VERSION 5.7 ;
  NOWIREEXTENSIONATPIN ON ;
  DIVIDERCHAR "/" ;
  BUSBITCHARS "[]" ;
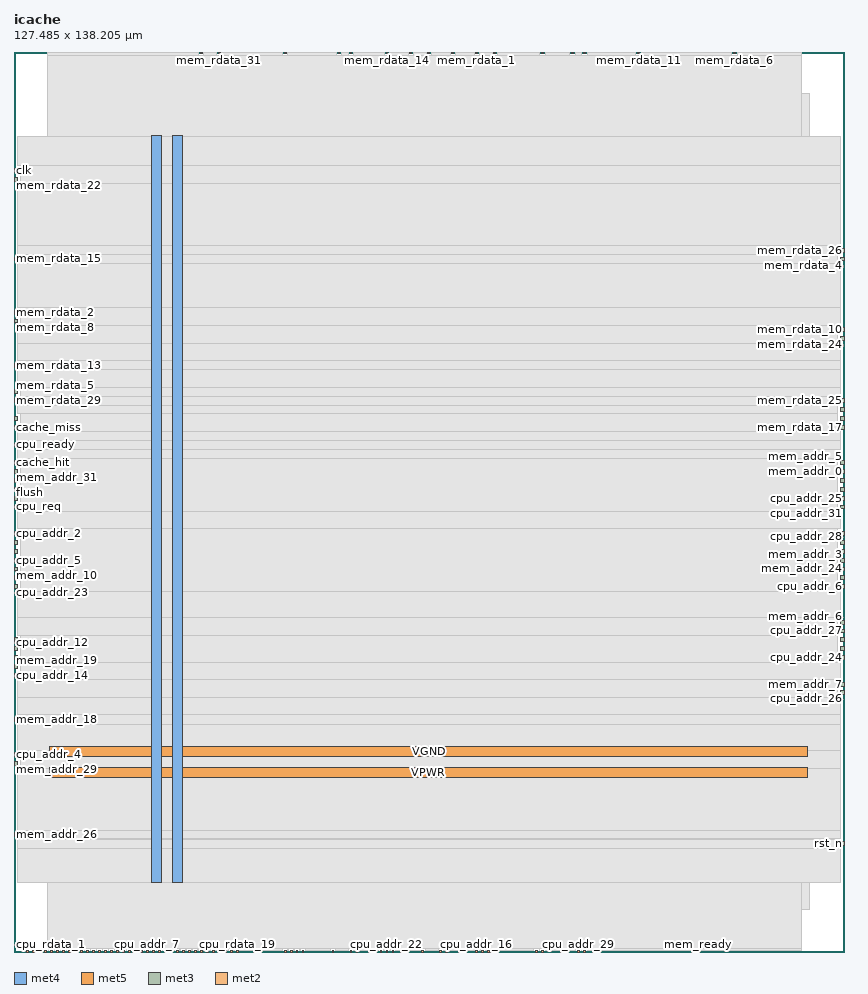
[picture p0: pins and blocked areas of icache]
MACRO icache
  CLASS BLOCK ;
  FOREIGN icache ;
  ORIGIN 0.000 0.000 ;
  SIZE 127.485 BY 138.205 ;
  PIN VGND
    DIRECTION INOUT ;
    USE GROUND ;
    PORT
      LAYER met4 ;
        RECT 24.340 10.640 25.940 125.360 ;
    END
    PORT
      LAYER met5 ;
        RECT 5.520 30.030 121.900 31.630 ;
    END
  END VGND
  PIN VPWR
    DIRECTION INOUT ;
    USE POWER ;
    PORT
      LAYER met4 ;
        RECT 21.040 10.640 22.640 125.360 ;
    END
    PORT
      LAYER met5 ;
        RECT 5.520 26.730 121.900 28.330 ;
    END
  END VPWR
  PIN cache_hit
    DIRECTION OUTPUT ;
    USE SIGNAL ;
    ANTENNAGATEAREA 0.434700 ;
    ANTENNADIFFAREA 1.137600 ;
    PORT
      LAYER met3 ;
        RECT 0.000 74.840 0.600 75.440 ;
    END
  END cache_hit
  PIN cache_miss
    DIRECTION OUTPUT ;
    USE SIGNAL ;
    ANTENNAGATEAREA 0.434700 ;
    ANTENNADIFFAREA 1.137600 ;
    PORT
      LAYER met3 ;
        RECT 0.000 80.280 0.600 80.880 ;
    END
  END cache_miss
  PIN clk
    DIRECTION INPUT ;
    USE SIGNAL ;
    ANTENNAGATEAREA 1.286700 ;
    ANTENNADIFFAREA 0.434700 ;
    PORT
      LAYER met3 ;
        RECT 0.000 119.720 0.600 120.320 ;
    END
  END clk
  PIN cpu_addr_0
    DIRECTION INPUT ;
    USE SIGNAL ;
    ANTENNAGATEAREA 0.647700 ;
    ANTENNADIFFAREA 0.434700 ;
    PORT
      LAYER met2 ;
        RECT 81.050 0.000 81.330 0.280 ;
    END
  END cpu_addr_0
  PIN cpu_addr_1
    DIRECTION INPUT ;
    USE SIGNAL ;
    ANTENNAGATEAREA 0.647700 ;
    ANTENNADIFFAREA 0.434700 ;
    PORT
      LAYER met2 ;
        RECT 59.890 0.000 60.170 0.280 ;
    END
  END cpu_addr_1
  PIN cpu_addr_10
    DIRECTION INPUT ;
    USE SIGNAL ;
    ANTENNAGATEAREA 0.647700 ;
    ANTENNADIFFAREA 0.434700 ;
    PORT
      LAYER met2 ;
        RECT 29.530 0.000 29.810 0.280 ;
    END
  END cpu_addr_10
  PIN cpu_addr_11
    DIRECTION INPUT ;
    USE SIGNAL ;
    ANTENNAGATEAREA 0.647700 ;
    ANTENNADIFFAREA 0.434700 ;
    PORT
      LAYER met2 ;
        RECT 72.770 0.000 73.050 0.280 ;
    END
  END cpu_addr_11
  PIN cpu_addr_12
    DIRECTION INPUT ;
    USE SIGNAL ;
    ANTENNAGATEAREA 0.647700 ;
    ANTENNADIFFAREA 0.434700 ;
    PORT
      LAYER met3 ;
        RECT 0.000 46.280 0.600 46.880 ;
    END
  END cpu_addr_12
  PIN cpu_addr_13
    DIRECTION INPUT ;
    USE SIGNAL ;
    ANTENNAGATEAREA 0.647700 ;
    ANTENNADIFFAREA 0.434700 ;
    PORT
      LAYER met2 ;
        RECT 56.210 0.000 56.490 0.280 ;
    END
  END cpu_addr_13
  PIN cpu_addr_14
    DIRECTION INPUT ;
    USE SIGNAL ;
    ANTENNAGATEAREA 0.647700 ;
    ANTENNADIFFAREA 0.434700 ;
    PORT
      LAYER met3 ;
        RECT 0.000 42.200 0.600 42.800 ;
    END
  END cpu_addr_14
  PIN cpu_addr_15
    DIRECTION INPUT ;
    USE SIGNAL ;
    ANTENNAGATEAREA 0.647700 ;
    ANTENNADIFFAREA 0.434700 ;
    PORT
      LAYER met2 ;
        RECT 28.610 0.000 28.890 0.280 ;
    END
  END cpu_addr_15
  PIN cpu_addr_16
    DIRECTION INPUT ;
    USE SIGNAL ;
    ANTENNAGATEAREA 0.647700 ;
    ANTENNADIFFAREA 0.434700 ;
    PORT
      LAYER met2 ;
        RECT 70.930 0.000 71.210 0.280 ;
    END
  END cpu_addr_16
  PIN cpu_addr_17
    DIRECTION INPUT ;
    USE SIGNAL ;
    ANTENNAGATEAREA 0.647700 ;
    ANTENNADIFFAREA 0.434700 ;
    PORT
      LAYER met2 ;
        RECT 65.410 0.000 65.690 0.280 ;
    END
  END cpu_addr_17
  PIN cpu_addr_18
    DIRECTION INPUT ;
    USE SIGNAL ;
    ANTENNAGATEAREA 0.647700 ;
    ANTENNADIFFAREA 0.434700 ;
    PORT
      LAYER met2 ;
        RECT 43.330 0.000 43.610 0.280 ;
    END
  END cpu_addr_18
  PIN cpu_addr_19
    DIRECTION INPUT ;
    USE SIGNAL ;
    ANTENNAGATEAREA 0.647700 ;
    ANTENNADIFFAREA 0.434700 ;
    PORT
      LAYER met2 ;
        RECT 80.130 0.000 80.410 0.280 ;
    END
  END cpu_addr_19
  PIN cpu_addr_2
    DIRECTION INPUT ;
    USE SIGNAL ;
    ANTENNAGATEAREA 0.647700 ;
    ANTENNADIFFAREA 0.434700 ;
    PORT
      LAYER met3 ;
        RECT 0.000 63.960 0.600 64.560 ;
    END
  END cpu_addr_2
  PIN cpu_addr_20
    DIRECTION INPUT ;
    USE SIGNAL ;
    ANTENNAGATEAREA 0.647700 ;
    ANTENNADIFFAREA 0.434700 ;
    PORT
      LAYER met2 ;
        RECT 51.610 0.000 51.890 0.280 ;
    END
  END cpu_addr_20
  PIN cpu_addr_21
    DIRECTION INPUT ;
    USE SIGNAL ;
    ANTENNAGATEAREA 0.647700 ;
    ANTENNADIFFAREA 0.434700 ;
    PORT
      LAYER met3 ;
        RECT 0.000 62.600 0.600 63.200 ;
    END
  END cpu_addr_21
  PIN cpu_addr_22
    DIRECTION INPUT ;
    USE SIGNAL ;
    ANTENNAGATEAREA 0.647700 ;
    ANTENNADIFFAREA 0.434700 ;
    PORT
      LAYER met2 ;
        RECT 57.130 0.000 57.410 0.280 ;
    END
  END cpu_addr_22
  PIN cpu_addr_23
    DIRECTION INPUT ;
    USE SIGNAL ;
    ANTENNAGATEAREA 0.647700 ;
    ANTENNADIFFAREA 0.434700 ;
    PORT
      LAYER met3 ;
        RECT 0.000 55.800 0.600 56.400 ;
    END
  END cpu_addr_23
  PIN cpu_addr_24
    DIRECTION INPUT ;
    USE SIGNAL ;
    ANTENNAGATEAREA 0.647700 ;
    ANTENNADIFFAREA 0.434700 ;
    PORT
      LAYER met3 ;
        RECT 126.885 44.920 127.485 45.520 ;
    END
  END cpu_addr_24
  PIN cpu_addr_25
    DIRECTION INPUT ;
    USE SIGNAL ;
    ANTENNAGATEAREA 0.647700 ;
    ANTENNADIFFAREA 0.434700 ;
    PORT
      LAYER met3 ;
        RECT 126.885 69.400 127.485 70.000 ;
    END
  END cpu_addr_25
  PIN cpu_addr_26
    DIRECTION INPUT ;
    USE SIGNAL ;
    ANTENNAGATEAREA 0.647700 ;
    ANTENNADIFFAREA 0.434700 ;
    PORT
      LAYER met3 ;
        RECT 126.885 39.480 127.485 40.080 ;
    END
  END cpu_addr_26
  PIN cpu_addr_27
    DIRECTION INPUT ;
    USE SIGNAL ;
    ANTENNAGATEAREA 0.647700 ;
    ANTENNADIFFAREA 0.434700 ;
    PORT
      LAYER met3 ;
        RECT 126.885 49.000 127.485 49.600 ;
    END
  END cpu_addr_27
  PIN cpu_addr_28
    DIRECTION INPUT ;
    USE SIGNAL ;
    ANTENNAGATEAREA 0.647700 ;
    ANTENNADIFFAREA 0.434700 ;
    PORT
      LAYER met3 ;
        RECT 126.885 62.600 127.485 63.200 ;
    END
  END cpu_addr_28
  PIN cpu_addr_29
    DIRECTION INPUT ;
    USE SIGNAL ;
    ANTENNAGATEAREA 0.647700 ;
    ANTENNADIFFAREA 0.434700 ;
    PORT
      LAYER met2 ;
        RECT 86.570 0.000 86.850 0.280 ;
    END
  END cpu_addr_29
  PIN cpu_addr_3
    DIRECTION INPUT ;
    USE SIGNAL ;
    ANTENNAGATEAREA 0.647700 ;
    ANTENNADIFFAREA 0.434700 ;
    PORT
      LAYER met3 ;
        RECT 0.000 44.920 0.600 45.520 ;
    END
  END cpu_addr_3
  PIN cpu_addr_30
    DIRECTION INPUT ;
    USE SIGNAL ;
    ANTENNAGATEAREA 0.647700 ;
    ANTENNADIFFAREA 0.434700 ;
    PORT
      LAYER met3 ;
        RECT 126.885 61.240 127.485 61.840 ;
    END
  END cpu_addr_30
  PIN cpu_addr_31
    DIRECTION INPUT ;
    USE SIGNAL ;
    ANTENNAGATEAREA 0.647700 ;
    ANTENNADIFFAREA 0.434700 ;
    PORT
      LAYER met3 ;
        RECT 126.885 68.040 127.485 68.640 ;
    END
  END cpu_addr_31
  PIN cpu_addr_4
    DIRECTION INPUT ;
    USE SIGNAL ;
    ANTENNAGATEAREA 0.647700 ;
    ANTENNADIFFAREA 0.434700 ;
    PORT
      LAYER met3 ;
        RECT 0.000 29.960 0.600 30.560 ;
    END
  END cpu_addr_4
  PIN cpu_addr_5
    DIRECTION INPUT ;
    USE SIGNAL ;
    ANTENNAGATEAREA 0.647700 ;
    ANTENNADIFFAREA 0.434700 ;
    PORT
      LAYER met3 ;
        RECT 0.000 59.880 0.600 60.480 ;
    END
  END cpu_addr_5
  PIN cpu_addr_6
    DIRECTION INPUT ;
    USE SIGNAL ;
    ANTENNAGATEAREA 0.647700 ;
    ANTENNADIFFAREA 0.434700 ;
    PORT
      LAYER met3 ;
        RECT 126.885 55.800 127.485 56.400 ;
    END
  END cpu_addr_6
  PIN cpu_addr_7
    DIRECTION INPUT ;
    USE SIGNAL ;
    ANTENNAGATEAREA 0.647700 ;
    ANTENNADIFFAREA 0.434700 ;
    PORT
      LAYER met2 ;
        RECT 20.330 0.000 20.610 0.280 ;
    END
  END cpu_addr_7
  PIN cpu_addr_8
    DIRECTION INPUT ;
    USE SIGNAL ;
    ANTENNAGATEAREA 0.647700 ;
    ANTENNADIFFAREA 0.434700 ;
    PORT
      LAYER met2 ;
        RECT 42.410 0.000 42.690 0.280 ;
    END
  END cpu_addr_8
  PIN cpu_addr_9
    DIRECTION INPUT ;
    USE SIGNAL ;
    ANTENNAGATEAREA 0.647700 ;
    ANTENNADIFFAREA 0.434700 ;
    PORT
      LAYER met3 ;
        RECT 126.885 57.160 127.485 57.760 ;
    END
  END cpu_addr_9
  PIN cpu_rdata_0
    DIRECTION OUTPUT ;
    USE SIGNAL ;
    PORT
      LAYER met2 ;
        RECT 3.770 0.000 4.050 0.280 ;
    END
  END cpu_rdata_0
  PIN cpu_rdata_1
    DIRECTION OUTPUT ;
    USE SIGNAL ;
    PORT
      LAYER met2 ;
        RECT 4.690 0.000 4.970 0.280 ;
    END
  END cpu_rdata_1
  PIN cpu_rdata_10
    DIRECTION OUTPUT ;
    USE SIGNAL ;
    PORT
      LAYER met2 ;
        RECT 5.610 0.000 5.890 0.280 ;
    END
  END cpu_rdata_10
  PIN cpu_rdata_11
    DIRECTION OUTPUT ;
    USE SIGNAL ;
    PORT
      LAYER met2 ;
        RECT 6.530 0.000 6.810 0.280 ;
    END
  END cpu_rdata_11
  PIN cpu_rdata_12
    DIRECTION OUTPUT ;
    USE SIGNAL ;
    PORT
      LAYER met2 ;
        RECT 7.450 0.000 7.730 0.280 ;
    END
  END cpu_rdata_12
  PIN cpu_rdata_13
    DIRECTION OUTPUT ;
    USE SIGNAL ;
    PORT
      LAYER met2 ;
        RECT 8.370 0.000 8.650 0.280 ;
    END
  END cpu_rdata_13
  PIN cpu_rdata_14
    DIRECTION OUTPUT ;
    USE SIGNAL ;
    PORT
      LAYER met2 ;
        RECT 9.290 0.000 9.570 0.280 ;
    END
  END cpu_rdata_14
  PIN cpu_rdata_15
    DIRECTION OUTPUT ;
    USE SIGNAL ;
    PORT
      LAYER met2 ;
        RECT 33.210 0.000 33.490 0.280 ;
    END
  END cpu_rdata_15
  PIN cpu_rdata_16
    DIRECTION OUTPUT ;
    USE SIGNAL ;
    PORT
      LAYER met2 ;
        RECT 10.210 0.000 10.490 0.280 ;
    END
  END cpu_rdata_16
  PIN cpu_rdata_17
    DIRECTION OUTPUT ;
    USE SIGNAL ;
    PORT
      LAYER met2 ;
        RECT 11.130 0.000 11.410 0.280 ;
    END
  END cpu_rdata_17
  PIN cpu_rdata_18
    DIRECTION OUTPUT ;
    USE SIGNAL ;
    PORT
      LAYER met2 ;
        RECT 12.050 0.000 12.330 0.280 ;
    END
  END cpu_rdata_18
  PIN cpu_rdata_19
    DIRECTION OUTPUT ;
    USE SIGNAL ;
    PORT
      LAYER met2 ;
        RECT 34.130 0.000 34.410 0.280 ;
    END
  END cpu_rdata_19
  PIN cpu_rdata_2
    DIRECTION OUTPUT ;
    USE SIGNAL ;
    PORT
      LAYER met2 ;
        RECT 12.970 0.000 13.250 0.280 ;
    END
  END cpu_rdata_2
  PIN cpu_rdata_20
    DIRECTION OUTPUT ;
    USE SIGNAL ;
    PORT
      LAYER met2 ;
        RECT 13.890 0.000 14.170 0.280 ;
    END
  END cpu_rdata_20
  PIN cpu_rdata_21
    DIRECTION OUTPUT ;
    USE SIGNAL ;
    PORT
      LAYER met2 ;
        RECT 14.810 0.000 15.090 0.280 ;
    END
  END cpu_rdata_21
  PIN cpu_rdata_22
    DIRECTION OUTPUT ;
    USE SIGNAL ;
    PORT
      LAYER met2 ;
        RECT 15.730 0.000 16.010 0.280 ;
    END
  END cpu_rdata_22
  PIN cpu_rdata_23
    DIRECTION OUTPUT ;
    USE SIGNAL ;
    PORT
      LAYER met2 ;
        RECT 16.650 0.000 16.930 0.280 ;
    END
  END cpu_rdata_23
  PIN cpu_rdata_24
    DIRECTION OUTPUT ;
    USE SIGNAL ;
    PORT
      LAYER met2 ;
        RECT 17.570 0.000 17.850 0.280 ;
    END
  END cpu_rdata_24
  PIN cpu_rdata_25
    DIRECTION OUTPUT ;
    USE SIGNAL ;
    PORT
      LAYER met2 ;
        RECT 18.490 0.000 18.770 0.280 ;
    END
  END cpu_rdata_25
  PIN cpu_rdata_26
    DIRECTION OUTPUT ;
    USE SIGNAL ;
    PORT
      LAYER met2 ;
        RECT 19.410 0.000 19.690 0.280 ;
    END
  END cpu_rdata_26
  PIN cpu_rdata_27
    DIRECTION OUTPUT ;
    USE SIGNAL ;
    PORT
      LAYER met2 ;
        RECT 21.250 0.000 21.530 0.280 ;
    END
  END cpu_rdata_27
  PIN cpu_rdata_28
    DIRECTION OUTPUT ;
    USE SIGNAL ;
    PORT
      LAYER met2 ;
        RECT 22.170 0.000 22.450 0.280 ;
    END
  END cpu_rdata_28
  PIN cpu_rdata_29
    DIRECTION OUTPUT ;
    USE SIGNAL ;
    PORT
      LAYER met2 ;
        RECT 23.090 0.000 23.370 0.280 ;
    END
  END cpu_rdata_29
  PIN cpu_rdata_3
    DIRECTION OUTPUT ;
    USE SIGNAL ;
    PORT
      LAYER met2 ;
        RECT 24.010 0.000 24.290 0.280 ;
    END
  END cpu_rdata_3
  PIN cpu_rdata_30
    DIRECTION OUTPUT ;
    USE SIGNAL ;
    PORT
      LAYER met2 ;
        RECT 24.930 0.000 25.210 0.280 ;
    END
  END cpu_rdata_30
  PIN cpu_rdata_31
    DIRECTION OUTPUT ;
    USE SIGNAL ;
    PORT
      LAYER met2 ;
        RECT 25.850 0.000 26.130 0.280 ;
    END
  END cpu_rdata_31
  PIN cpu_rdata_4
    DIRECTION OUTPUT ;
    USE SIGNAL ;
    PORT
      LAYER met2 ;
        RECT 26.770 0.000 27.050 0.280 ;
    END
  END cpu_rdata_4
  PIN cpu_rdata_5
    DIRECTION OUTPUT ;
    USE SIGNAL ;
    PORT
      LAYER met2 ;
        RECT 27.690 0.000 27.970 0.280 ;
    END
  END cpu_rdata_5
  PIN cpu_rdata_6
    DIRECTION OUTPUT ;
    USE SIGNAL ;
    PORT
      LAYER met2 ;
        RECT 1.930 0.000 2.210 0.280 ;
    END
  END cpu_rdata_6
  PIN cpu_rdata_7
    DIRECTION OUTPUT ;
    USE SIGNAL ;
    PORT
      LAYER met2 ;
        RECT 2.850 0.000 3.130 0.280 ;
    END
  END cpu_rdata_7
  PIN cpu_rdata_8
    DIRECTION OUTPUT ;
    USE SIGNAL ;
    PORT
      LAYER met2 ;
        RECT 31.370 0.000 31.650 0.280 ;
    END
  END cpu_rdata_8
  PIN cpu_rdata_9
    DIRECTION OUTPUT ;
    USE SIGNAL ;
    PORT
      LAYER met2 ;
        RECT 32.290 0.000 32.570 0.280 ;
    END
  END cpu_rdata_9
  PIN cpu_ready
    DIRECTION OUTPUT ;
    USE SIGNAL ;
    ANTENNAGATEAREA 0.434700 ;
    ANTENNADIFFAREA 1.137600 ;
    PORT
      LAYER met3 ;
        RECT 0.000 77.560 0.600 78.160 ;
    END
  END cpu_ready
  PIN cpu_req
    DIRECTION INPUT ;
    USE SIGNAL ;
    ANTENNAGATEAREA 0.647700 ;
    ANTENNADIFFAREA 0.434700 ;
    PORT
      LAYER met3 ;
        RECT 0.000 68.040 0.600 68.640 ;
    END
  END cpu_req
  PIN flush
    DIRECTION INPUT ;
    USE SIGNAL ;
    ANTENNAGATEAREA 0.647700 ;
    ANTENNADIFFAREA 0.434700 ;
    PORT
      LAYER met3 ;
        RECT 0.000 69.400 0.600 70.000 ;
    END
  END flush
  PIN mem_addr_0
    DIRECTION OUTPUT ;
    USE SIGNAL ;
    ANTENNAGATEAREA 0.434700 ;
    ANTENNADIFFAREA 1.137600 ;
    PORT
      LAYER met3 ;
        RECT 126.885 73.480 127.485 74.080 ;
    END
  END mem_addr_0
  PIN mem_addr_1
    DIRECTION OUTPUT ;
    USE SIGNAL ;
    ANTENNAGATEAREA 0.434700 ;
    ANTENNADIFFAREA 1.137600 ;
    PORT
      LAYER met3 ;
        RECT 0.000 72.120 0.600 72.720 ;
    END
  END mem_addr_1
  PIN mem_addr_10
    DIRECTION OUTPUT ;
    USE SIGNAL ;
    ANTENNAGATEAREA 0.434700 ;
    ANTENNADIFFAREA 1.137600 ;
    PORT
      LAYER met3 ;
        RECT 0.000 58.520 0.600 59.120 ;
    END
  END mem_addr_10
  PIN mem_addr_11
    DIRECTION OUTPUT ;
    USE SIGNAL ;
    ANTENNAGATEAREA 0.434700 ;
    ANTENNADIFFAREA 1.137600 ;
    PORT
      LAYER met2 ;
        RECT 52.530 0.000 52.810 0.280 ;
    END
  END mem_addr_11
  PIN mem_addr_12
    DIRECTION OUTPUT ;
    USE SIGNAL ;
    ANTENNAGATEAREA 0.434700 ;
    ANTENNADIFFAREA 1.137600 ;
    PORT
      LAYER met2 ;
        RECT 62.650 0.000 62.930 0.280 ;
    END
  END mem_addr_12
  PIN mem_addr_13
    DIRECTION OUTPUT ;
    USE SIGNAL ;
    ANTENNAGATEAREA 0.434700 ;
    ANTENNADIFFAREA 1.137600 ;
    PORT
      LAYER met2 ;
        RECT 48.850 0.000 49.130 0.280 ;
    END
  END mem_addr_13
  PIN mem_addr_14
    DIRECTION OUTPUT ;
    USE SIGNAL ;
    ANTENNAGATEAREA 0.434700 ;
    ANTENNADIFFAREA 1.137600 ;
    PORT
      LAYER met3 ;
        RECT 126.885 47.640 127.485 48.240 ;
    END
  END mem_addr_14
  PIN mem_addr_15
    DIRECTION OUTPUT ;
    USE SIGNAL ;
    ANTENNAGATEAREA 0.434700 ;
    ANTENNADIFFAREA 1.137600 ;
    PORT
      LAYER met2 ;
        RECT 44.250 0.000 44.530 0.280 ;
    END
  END mem_addr_15
  PIN mem_addr_16
    DIRECTION OUTPUT ;
    USE SIGNAL ;
    ANTENNAGATEAREA 0.434700 ;
    ANTENNADIFFAREA 1.137600 ;
    PORT
      LAYER met2 ;
        RECT 66.330 0.000 66.610 0.280 ;
    END
  END mem_addr_16
  PIN mem_addr_17
    DIRECTION OUTPUT ;
    USE SIGNAL ;
    ANTENNAGATEAREA 0.434700 ;
    ANTENNADIFFAREA 1.137600 ;
    PORT
      LAYER met2 ;
        RECT 69.090 0.000 69.370 0.280 ;
    END
  END mem_addr_17
  PIN mem_addr_18
    DIRECTION OUTPUT ;
    USE SIGNAL ;
    ANTENNAGATEAREA 0.434700 ;
    ANTENNADIFFAREA 1.137600 ;
    PORT
      LAYER met3 ;
        RECT 0.000 35.400 0.600 36.000 ;
    END
  END mem_addr_18
  PIN mem_addr_19
    DIRECTION OUTPUT ;
    USE SIGNAL ;
    ANTENNAGATEAREA 0.434700 ;
    ANTENNADIFFAREA 1.137600 ;
    PORT
      LAYER met3 ;
        RECT 0.000 43.560 0.600 44.160 ;
    END
  END mem_addr_19
  PIN mem_addr_2
    DIRECTION OUTPUT ;
    USE SIGNAL ;
    ANTENNAGATEAREA 0.434700 ;
    ANTENNADIFFAREA 1.137600 ;
    PORT
      LAYER met3 ;
        RECT 126.885 70.760 127.485 71.360 ;
    END
  END mem_addr_2
  PIN mem_addr_20
    DIRECTION OUTPUT ;
    USE SIGNAL ;
    ANTENNAGATEAREA 0.434700 ;
    ANTENNADIFFAREA 1.137600 ;
    PORT
      LAYER met2 ;
        RECT 58.050 0.000 58.330 0.280 ;
    END
  END mem_addr_20
  PIN mem_addr_21
    DIRECTION OUTPUT ;
    USE SIGNAL ;
    ANTENNAGATEAREA 0.434700 ;
    ANTENNADIFFAREA 1.137600 ;
    PORT
      LAYER met3 ;
        RECT 0.000 57.160 0.600 57.760 ;
    END
  END mem_addr_21
  PIN mem_addr_22
    DIRECTION OUTPUT ;
    USE SIGNAL ;
    ANTENNAGATEAREA 0.434700 ;
    ANTENNADIFFAREA 1.137600 ;
    PORT
      LAYER met2 ;
        RECT 71.850 0.000 72.130 0.280 ;
    END
  END mem_addr_22
  PIN mem_addr_23
    DIRECTION OUTPUT ;
    USE SIGNAL ;
    ANTENNAGATEAREA 0.434700 ;
    ANTENNADIFFAREA 1.137600 ;
    PORT
      LAYER met2 ;
        RECT 30.450 0.000 30.730 0.280 ;
    END
  END mem_addr_23
  PIN mem_addr_24
    DIRECTION OUTPUT ;
    USE SIGNAL ;
    ANTENNAGATEAREA 0.434700 ;
    ANTENNADIFFAREA 1.137600 ;
    PORT
      LAYER met3 ;
        RECT 126.885 58.520 127.485 59.120 ;
    END
  END mem_addr_24
  PIN mem_addr_25
    DIRECTION OUTPUT ;
    USE SIGNAL ;
    ANTENNAGATEAREA 0.434700 ;
    ANTENNADIFFAREA 1.137600 ;
    PORT
      LAYER met2 ;
        RECT 41.490 0.000 41.770 0.280 ;
    END
  END mem_addr_25
  PIN mem_addr_26
    DIRECTION OUTPUT ;
    USE SIGNAL ;
    ANTENNAGATEAREA 0.434700 ;
    ANTENNADIFFAREA 1.137600 ;
    PORT
      LAYER met3 ;
        RECT 0.000 17.720 0.600 18.320 ;
    END
  END mem_addr_26
  PIN mem_addr_27
    DIRECTION OUTPUT ;
    USE SIGNAL ;
    ANTENNAGATEAREA 0.434700 ;
    ANTENNADIFFAREA 1.137600 ;
    PORT
      LAYER met3 ;
        RECT 126.885 63.960 127.485 64.560 ;
    END
  END mem_addr_27
  PIN mem_addr_28
    DIRECTION OUTPUT ;
    USE SIGNAL ;
    ANTENNAGATEAREA 0.434700 ;
    ANTENNADIFFAREA 1.137600 ;
    PORT
      LAYER met3 ;
        RECT 0.000 61.240 0.600 61.840 ;
    END
  END mem_addr_28
  PIN mem_addr_29
    DIRECTION OUTPUT ;
    USE SIGNAL ;
    ANTENNAGATEAREA 0.434700 ;
    ANTENNADIFFAREA 1.137600 ;
    PORT
      LAYER met3 ;
        RECT 0.000 28.600 0.600 29.200 ;
    END
  END mem_addr_29
  PIN mem_addr_3
    DIRECTION OUTPUT ;
    USE SIGNAL ;
    ANTENNAGATEAREA 0.434700 ;
    ANTENNADIFFAREA 1.137600 ;
    PORT
      LAYER met3 ;
        RECT 126.885 59.880 127.485 60.480 ;
    END
  END mem_addr_3
  PIN mem_addr_30
    DIRECTION OUTPUT ;
    USE SIGNAL ;
    ANTENNAGATEAREA 0.434700 ;
    ANTENNADIFFAREA 1.137600 ;
    PORT
      LAYER met3 ;
        RECT 0.000 47.640 0.600 48.240 ;
    END
  END mem_addr_30
  PIN mem_addr_31
    DIRECTION OUTPUT ;
    USE SIGNAL ;
    ANTENNAGATEAREA 0.434700 ;
    ANTENNADIFFAREA 1.137600 ;
    PORT
      LAYER met3 ;
        RECT 0.000 73.480 0.600 74.080 ;
    END
  END mem_addr_31
  PIN mem_addr_4
    DIRECTION OUTPUT ;
    USE SIGNAL ;
    ANTENNAGATEAREA 0.434700 ;
    ANTENNADIFFAREA 1.137600 ;
    PORT
      LAYER met2 ;
        RECT 87.490 0.000 87.770 0.280 ;
    END
  END mem_addr_4
  PIN mem_addr_5
    DIRECTION OUTPUT ;
    USE SIGNAL ;
    ANTENNAGATEAREA 0.434700 ;
    ANTENNADIFFAREA 1.137600 ;
    PORT
      LAYER met3 ;
        RECT 126.885 74.840 127.485 75.440 ;
    END
  END mem_addr_5
  PIN mem_addr_6
    DIRECTION OUTPUT ;
    USE SIGNAL ;
    ANTENNAGATEAREA 0.434700 ;
    ANTENNADIFFAREA 1.137600 ;
    PORT
      LAYER met3 ;
        RECT 126.885 50.360 127.485 50.960 ;
    END
  END mem_addr_6
  PIN mem_addr_7
    DIRECTION OUTPUT ;
    USE SIGNAL ;
    ANTENNAGATEAREA 0.434700 ;
    ANTENNADIFFAREA 1.137600 ;
    PORT
      LAYER met3 ;
        RECT 126.885 40.840 127.485 41.440 ;
    END
  END mem_addr_7
  PIN mem_addr_8
    DIRECTION OUTPUT ;
    USE SIGNAL ;
    ANTENNAGATEAREA 0.434700 ;
    ANTENNADIFFAREA 1.137600 ;
    PORT
      LAYER met3 ;
        RECT 126.885 72.120 127.485 72.720 ;
    END
  END mem_addr_8
  PIN mem_addr_9
    DIRECTION OUTPUT ;
    USE SIGNAL ;
    ANTENNAGATEAREA 0.434700 ;
    ANTENNADIFFAREA 1.137600 ;
    PORT
      LAYER met3 ;
        RECT 126.885 46.280 127.485 46.880 ;
    END
  END mem_addr_9
  PIN mem_rdata_0
    DIRECTION INPUT ;
    USE SIGNAL ;
    ANTENNAGATEAREA 0.647700 ;
    ANTENNADIFFAREA 0.434700 ;
    PORT
      LAYER met2 ;
        RECT 60.810 137.925 61.090 138.205 ;
    END
  END mem_rdata_0
  PIN mem_rdata_1
    DIRECTION INPUT ;
    USE SIGNAL ;
    ANTENNAGATEAREA 0.647700 ;
    ANTENNADIFFAREA 0.434700 ;
    PORT
      LAYER met2 ;
        RECT 70.930 137.925 71.210 138.205 ;
    END
  END mem_rdata_1
  PIN mem_rdata_10
    DIRECTION INPUT ;
    USE SIGNAL ;
    ANTENNAGATEAREA 0.647700 ;
    ANTENNADIFFAREA 0.434700 ;
    PORT
      LAYER met3 ;
        RECT 126.885 95.240 127.485 95.840 ;
    END
  END mem_rdata_10
  PIN mem_rdata_11
    DIRECTION INPUT ;
    USE SIGNAL ;
    ANTENNAGATEAREA 0.647700 ;
    ANTENNADIFFAREA 0.434700 ;
    PORT
      LAYER met2 ;
        RECT 95.770 137.925 96.050 138.205 ;
    END
  END mem_rdata_11
  PIN mem_rdata_12
    DIRECTION INPUT ;
    USE SIGNAL ;
    ANTENNAGATEAREA 0.647700 ;
    ANTENNADIFFAREA 0.434700 ;
    PORT
      LAYER met2 ;
        RECT 85.650 137.925 85.930 138.205 ;
    END
  END mem_rdata_12
  PIN mem_rdata_13
    DIRECTION INPUT ;
    USE SIGNAL ;
    ANTENNAGATEAREA 0.647700 ;
    ANTENNADIFFAREA 0.434700 ;
    PORT
      LAYER met3 ;
        RECT 0.000 89.800 0.600 90.400 ;
    END
  END mem_rdata_13
  PIN mem_rdata_14
    DIRECTION INPUT ;
    USE SIGNAL ;
    ANTENNAGATEAREA 0.647700 ;
    ANTENNADIFFAREA 0.434700 ;
    PORT
      LAYER met2 ;
        RECT 57.130 137.925 57.410 138.205 ;
    END
  END mem_rdata_14
  PIN mem_rdata_15
    DIRECTION INPUT ;
    USE SIGNAL ;
    ANTENNAGATEAREA 0.647700 ;
    ANTENNADIFFAREA 0.434700 ;
    PORT
      LAYER met3 ;
        RECT 0.000 106.120 0.600 106.720 ;
    END
  END mem_rdata_15
  PIN mem_rdata_16
    DIRECTION INPUT ;
    USE SIGNAL ;
    ANTENNAGATEAREA 0.647700 ;
    ANTENNADIFFAREA 0.434700 ;
    PORT
      LAYER met2 ;
        RECT 51.610 137.925 51.890 138.205 ;
    END
  END mem_rdata_16
  PIN mem_rdata_17
    DIRECTION INPUT ;
    USE SIGNAL ;
    ANTENNAGATEAREA 0.647700 ;
    ANTENNADIFFAREA 0.434700 ;
    PORT
      LAYER met3 ;
        RECT 126.885 80.280 127.485 80.880 ;
    END
  END mem_rdata_17
  PIN mem_rdata_18
    DIRECTION INPUT ;
    USE SIGNAL ;
    ANTENNAGATEAREA 0.647700 ;
    ANTENNADIFFAREA 0.434700 ;
    PORT
      LAYER met2 ;
        RECT 49.770 137.925 50.050 138.205 ;
    END
  END mem_rdata_18
  PIN mem_rdata_19
    DIRECTION INPUT ;
    USE SIGNAL ;
    ANTENNAGATEAREA 0.647700 ;
    ANTENNADIFFAREA 0.434700 ;
    PORT
      LAYER met2 ;
        RECT 87.490 137.925 87.770 138.205 ;
    END
  END mem_rdata_19
  PIN mem_rdata_2
    DIRECTION INPUT ;
    USE SIGNAL ;
    ANTENNAGATEAREA 0.647700 ;
    ANTENNADIFFAREA 0.434700 ;
    PORT
      LAYER met3 ;
        RECT 0.000 97.960 0.600 98.560 ;
    END
  END mem_rdata_2
  PIN mem_rdata_20
    DIRECTION INPUT ;
    USE SIGNAL ;
    ANTENNAGATEAREA 0.647700 ;
    ANTENNADIFFAREA 0.434700 ;
    PORT
      LAYER met2 ;
        RECT 28.610 137.925 28.890 138.205 ;
    END
  END mem_rdata_20
  PIN mem_rdata_21
    DIRECTION INPUT ;
    USE SIGNAL ;
    ANTENNAGATEAREA 0.647700 ;
    ANTENNADIFFAREA 0.434700 ;
    PORT
      LAYER met2 ;
        RECT 63.570 137.925 63.850 138.205 ;
    END
  END mem_rdata_21
  PIN mem_rdata_22
    DIRECTION INPUT ;
    USE SIGNAL ;
    ANTENNAGATEAREA 0.647700 ;
    ANTENNADIFFAREA 0.434700 ;
    PORT
      LAYER met3 ;
        RECT 0.000 118.360 0.600 118.960 ;
    END
  END mem_rdata_22
  PIN mem_rdata_23
    DIRECTION INPUT ;
    USE SIGNAL ;
    ANTENNAGATEAREA 0.647700 ;
    ANTENNADIFFAREA 0.434700 ;
    PORT
      LAYER met2 ;
        RECT 41.490 137.925 41.770 138.205 ;
    END
  END mem_rdata_23
  PIN mem_rdata_24
    DIRECTION INPUT ;
    USE SIGNAL ;
    ANTENNAGATEAREA 0.647700 ;
    ANTENNADIFFAREA 0.434700 ;
    PORT
      LAYER met3 ;
        RECT 126.885 93.880 127.485 94.480 ;
    END
  END mem_rdata_24
  PIN mem_rdata_25
    DIRECTION INPUT ;
    USE SIGNAL ;
    ANTENNAGATEAREA 0.647700 ;
    ANTENNADIFFAREA 0.434700 ;
    PORT
      LAYER met3 ;
        RECT 126.885 84.360 127.485 84.960 ;
    END
  END mem_rdata_25
  PIN mem_rdata_26
    DIRECTION INPUT ;
    USE SIGNAL ;
    ANTENNAGATEAREA 0.647700 ;
    ANTENNADIFFAREA 0.434700 ;
    PORT
      LAYER met3 ;
        RECT 126.885 107.480 127.485 108.080 ;
    END
  END mem_rdata_26
  PIN mem_rdata_27
    DIRECTION INPUT ;
    USE SIGNAL ;
    ANTENNAGATEAREA 0.647700 ;
    ANTENNADIFFAREA 0.434700 ;
    PORT
      LAYER met3 ;
        RECT 126.885 81.640 127.485 82.240 ;
    END
  END mem_rdata_27
  PIN mem_rdata_28
    DIRECTION INPUT ;
    USE SIGNAL ;
    ANTENNAGATEAREA 0.647700 ;
    ANTENNADIFFAREA 0.434700 ;
    PORT
      LAYER met2 ;
        RECT 81.050 137.925 81.330 138.205 ;
    END
  END mem_rdata_28
  PIN mem_rdata_29
    DIRECTION INPUT ;
    USE SIGNAL ;
    ANTENNAGATEAREA 0.647700 ;
    ANTENNADIFFAREA 0.434700 ;
    PORT
      LAYER met3 ;
        RECT 0.000 84.360 0.600 84.960 ;
    END
  END mem_rdata_29
  PIN mem_rdata_3
    DIRECTION INPUT ;
    USE SIGNAL ;
    ANTENNAGATEAREA 0.647700 ;
    ANTENNADIFFAREA 0.434700 ;
    PORT
      LAYER met3 ;
        RECT 0.000 81.640 0.600 82.240 ;
    END
  END mem_rdata_3
  PIN mem_rdata_30
    DIRECTION INPUT ;
    USE SIGNAL ;
    ANTENNAGATEAREA 0.647700 ;
    ANTENNADIFFAREA 0.434700 ;
    PORT
      LAYER met3 ;
        RECT 126.885 83.000 127.485 83.600 ;
    END
  END mem_rdata_30
  PIN mem_rdata_31
    DIRECTION INPUT ;
    USE SIGNAL ;
    ANTENNAGATEAREA 0.647700 ;
    ANTENNADIFFAREA 0.434700 ;
    PORT
      LAYER met2 ;
        RECT 31.370 137.925 31.650 138.205 ;
    END
  END mem_rdata_31
  PIN mem_rdata_4
    DIRECTION INPUT ;
    USE SIGNAL ;
    ANTENNAGATEAREA 0.647700 ;
    ANTENNADIFFAREA 0.434700 ;
    PORT
      LAYER met3 ;
        RECT 126.885 106.120 127.485 106.720 ;
    END
  END mem_rdata_4
  PIN mem_rdata_5
    DIRECTION INPUT ;
    USE SIGNAL ;
    ANTENNAGATEAREA 0.647700 ;
    ANTENNADIFFAREA 0.434700 ;
    PORT
      LAYER met3 ;
        RECT 0.000 85.720 0.600 86.320 ;
    END
  END mem_rdata_5
  PIN mem_rdata_6
    DIRECTION INPUT ;
    USE SIGNAL ;
    ANTENNAGATEAREA 0.647700 ;
    ANTENNADIFFAREA 0.434700 ;
    PORT
      LAYER met2 ;
        RECT 110.490 137.925 110.770 138.205 ;
    END
  END mem_rdata_6
  PIN mem_rdata_7
    DIRECTION INPUT ;
    USE SIGNAL ;
    ANTENNAGATEAREA 0.647700 ;
    ANTENNADIFFAREA 0.434700 ;
    PORT
      LAYER met2 ;
        RECT 67.250 137.925 67.530 138.205 ;
    END
  END mem_rdata_7
  PIN mem_rdata_8
    DIRECTION INPUT ;
    USE SIGNAL ;
    ANTENNAGATEAREA 0.647700 ;
    ANTENNADIFFAREA 0.434700 ;
    PORT
      LAYER met3 ;
        RECT 0.000 96.600 0.600 97.200 ;
    END
  END mem_rdata_8
  PIN mem_rdata_9
    DIRECTION INPUT ;
    USE SIGNAL ;
    ANTENNAGATEAREA 0.647700 ;
    ANTENNADIFFAREA 0.434700 ;
    PORT
      LAYER met2 ;
        RECT 73.690 137.925 73.970 138.205 ;
    END
  END mem_rdata_9
  PIN mem_ready
    DIRECTION INPUT ;
    USE SIGNAL ;
    ANTENNAGATEAREA 0.647700 ;
    ANTENNADIFFAREA 0.434700 ;
    PORT
      LAYER met2 ;
        RECT 104.970 0.000 105.250 0.280 ;
    END
  END mem_ready
  PIN mem_req
    DIRECTION OUTPUT ;
    USE SIGNAL ;
    ANTENNAGATEAREA 0.434700 ;
    ANTENNADIFFAREA 1.137600 ;
    PORT
      LAYER met3 ;
        RECT 0.000 70.760 0.600 71.360 ;
    END
  END mem_req
  PIN rst_n
    DIRECTION INPUT ;
    USE SIGNAL ;
    ANTENNAGATEAREA 0.647700 ;
    ANTENNADIFFAREA 0.434700 ;
    PORT
      LAYER met3 ;
        RECT 126.885 16.360 127.485 16.960 ;
    END
  END rst_n
  OBS
      LAYER nwell ;
        RECT 5.330 10.795 122.090 125.205 ;
      LAYER li1 ;
        RECT 5.520 10.795 121.900 125.205 ;
      LAYER met1 ;
        RECT 5.130 6.500 122.200 131.880 ;
      LAYER met2 ;
        RECT 5.150 137.645 28.330 138.135 ;
        RECT 29.170 137.645 31.090 138.135 ;
        RECT 31.930 137.645 41.210 138.135 ;
        RECT 42.050 137.645 49.490 138.135 ;
        RECT 50.330 137.645 51.330 138.135 ;
        RECT 52.170 137.645 56.850 138.135 ;
        RECT 57.690 137.645 60.530 138.135 ;
        RECT 61.370 137.645 63.290 138.135 ;
        RECT 64.130 137.645 66.970 138.135 ;
        RECT 67.810 137.645 70.650 138.135 ;
        RECT 71.490 137.645 73.410 138.135 ;
        RECT 74.250 137.645 80.770 138.135 ;
        RECT 81.610 137.645 85.370 138.135 ;
        RECT 86.210 137.645 87.210 138.135 ;
        RECT 88.050 137.645 95.490 138.135 ;
        RECT 96.330 137.645 110.210 138.135 ;
        RECT 111.050 137.645 120.890 138.135 ;
        RECT 5.150 0.560 120.890 137.645 ;
        RECT 5.250 0.280 5.330 0.560 ;
        RECT 6.170 0.280 6.250 0.560 ;
        RECT 7.090 0.280 7.170 0.560 ;
        RECT 8.010 0.280 8.090 0.560 ;
        RECT 8.930 0.280 9.010 0.560 ;
        RECT 9.850 0.280 9.930 0.560 ;
        RECT 10.770 0.280 10.850 0.560 ;
        RECT 11.690 0.280 11.770 0.560 ;
        RECT 12.610 0.280 12.690 0.560 ;
        RECT 13.530 0.280 13.610 0.560 ;
        RECT 14.450 0.280 14.530 0.560 ;
        RECT 15.370 0.280 15.450 0.560 ;
        RECT 16.290 0.280 16.370 0.560 ;
        RECT 17.210 0.280 17.290 0.560 ;
        RECT 18.130 0.280 18.210 0.560 ;
        RECT 19.050 0.280 19.130 0.560 ;
        RECT 19.970 0.280 20.050 0.560 ;
        RECT 20.890 0.280 20.970 0.560 ;
        RECT 21.810 0.280 21.890 0.560 ;
        RECT 22.730 0.280 22.810 0.560 ;
        RECT 23.650 0.280 23.730 0.560 ;
        RECT 24.570 0.280 24.650 0.560 ;
        RECT 25.490 0.280 25.570 0.560 ;
        RECT 26.410 0.280 26.490 0.560 ;
        RECT 27.330 0.280 27.410 0.560 ;
        RECT 28.250 0.280 28.330 0.560 ;
        RECT 29.170 0.280 29.250 0.560 ;
        RECT 30.090 0.280 30.170 0.560 ;
        RECT 31.010 0.280 31.090 0.560 ;
        RECT 31.930 0.280 32.010 0.560 ;
        RECT 32.850 0.280 32.930 0.560 ;
        RECT 33.770 0.280 33.850 0.560 ;
        RECT 34.690 0.280 41.210 0.560 ;
        RECT 42.050 0.280 42.130 0.560 ;
        RECT 42.970 0.280 43.050 0.560 ;
        RECT 43.890 0.280 43.970 0.560 ;
        RECT 44.810 0.280 48.570 0.560 ;
        RECT 49.410 0.280 51.330 0.560 ;
        RECT 52.170 0.280 52.250 0.560 ;
        RECT 53.090 0.280 55.930 0.560 ;
        RECT 56.770 0.280 56.850 0.560 ;
        RECT 57.690 0.280 57.770 0.560 ;
        RECT 58.610 0.280 59.610 0.560 ;
        RECT 60.450 0.280 62.370 0.560 ;
        RECT 63.210 0.280 65.130 0.560 ;
        RECT 65.970 0.280 66.050 0.560 ;
        RECT 66.890 0.280 68.810 0.560 ;
        RECT 69.650 0.280 70.650 0.560 ;
        RECT 71.490 0.280 71.570 0.560 ;
        RECT 72.410 0.280 72.490 0.560 ;
        RECT 73.330 0.280 79.850 0.560 ;
        RECT 80.690 0.280 80.770 0.560 ;
        RECT 81.610 0.280 86.290 0.560 ;
        RECT 87.130 0.280 87.210 0.560 ;
        RECT 88.050 0.280 104.690 0.560 ;
        RECT 105.530 0.280 120.890 0.560 ;
      LAYER met3 ;
        RECT 0.600 120.720 126.885 125.285 ;
        RECT 1.000 117.960 126.885 120.720 ;
        RECT 0.600 108.480 126.885 117.960 ;
        RECT 0.600 107.120 126.485 108.480 ;
        RECT 1.000 105.720 126.485 107.120 ;
        RECT 0.600 98.960 126.885 105.720 ;
        RECT 1.000 96.240 126.885 98.960 ;
        RECT 1.000 96.200 126.485 96.240 ;
        RECT 0.600 93.480 126.485 96.200 ;
        RECT 0.600 90.800 126.885 93.480 ;
        RECT 1.000 89.400 126.885 90.800 ;
        RECT 0.600 86.720 126.885 89.400 ;
        RECT 1.000 85.360 126.885 86.720 ;
        RECT 1.000 83.960 126.485 85.360 ;
        RECT 0.600 82.640 126.485 83.960 ;
        RECT 1.000 79.880 126.485 82.640 ;
        RECT 0.600 78.560 126.885 79.880 ;
        RECT 1.000 77.160 126.885 78.560 ;
        RECT 0.600 75.840 126.885 77.160 ;
        RECT 1.000 67.640 126.485 75.840 ;
        RECT 0.600 64.960 126.885 67.640 ;
        RECT 1.000 55.400 126.485 64.960 ;
        RECT 0.600 51.360 126.885 55.400 ;
        RECT 0.600 48.640 126.485 51.360 ;
        RECT 1.000 44.520 126.485 48.640 ;
        RECT 1.000 41.840 126.885 44.520 ;
        RECT 1.000 41.800 126.485 41.840 ;
        RECT 0.600 39.080 126.485 41.800 ;
        RECT 0.600 36.400 126.885 39.080 ;
        RECT 1.000 35.000 126.885 36.400 ;
        RECT 0.600 30.960 126.885 35.000 ;
        RECT 1.000 28.200 126.885 30.960 ;
        RECT 0.600 18.720 126.885 28.200 ;
        RECT 1.000 17.360 126.885 18.720 ;
        RECT 1.000 17.320 126.485 17.360 ;
        RECT 0.600 15.960 126.485 17.320 ;
        RECT 0.600 10.715 126.885 15.960 ;
  END
END icache
END LIBRARY

